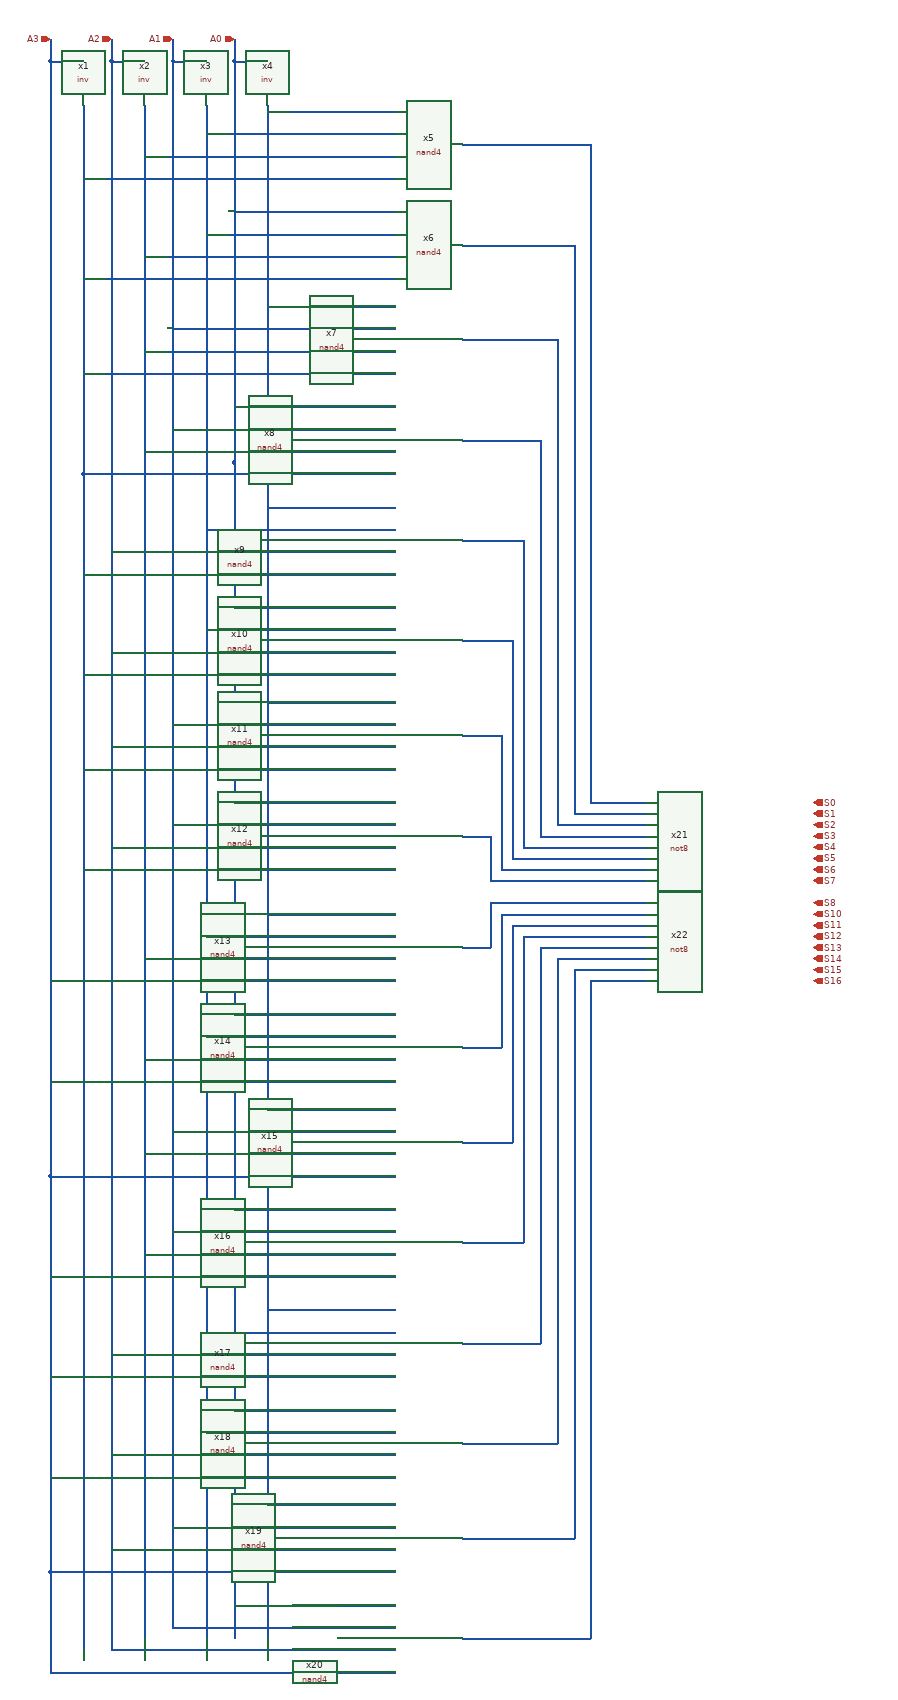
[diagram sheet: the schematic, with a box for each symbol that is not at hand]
v {xschem version=3.4.6 file_version=1.2}
G {}
K {}
V {}
S {}
E {}
N -230 -310 -230 -270 {lab=A3}
N -230 -270 -170 -270 {lab=A3}
N -120 -310 -120 -270 {lab=A2}
N -110 -270 -60 -270 {lab=A2}
N -10 -310 -10 -270 {lab=A1}
N -0 -270 50 -270 {lab=A1}
N 100 -310 100 -270 {lab=A0}
N 110 -270 160 -270 {lab=A0}
N -230 -270 -230 270 {lab=A3}
N -170 -190 -170 260 {lab=#net1}
N -170 260 -170 270 {lab=#net1}
N -120 -270 -120 270 {lab=A2}
N -60 -190 -60 260 {lab=#net2}
N -60 260 -60 270 {lab=#net2}
N 50 -190 50 260 {lab=#net3}
N 50 260 50 270 {lab=#net3}
N 100 -270 100 270 {lab=A0}
N 100 -270 110 -270 {lab=A0}
N -10 -270 0 -270 {lab=A1}
N -120 -270 -110 -270 {lab=A2}
N 160 -190 160 260 {lab=#net4}
N 160 260 160 270 {lab=#net4}
N 160 -180 390 -180 {lab=#net4}
N 50 -140 390 -140 {lab=#net3}
N -60 -100 390 -100 {lab=#net2}
N -170 -60 390 -60 {lab=#net1}
N 100 -0 390 0 {lab=A0}
N 50 40 390 40 {lab=#net3}
N -60 80 390 80 {lab=#net2}
N -170 120 390 120 {lab=#net1}
N 160 170 390 170 {lab=#net4}
N -10 210 390 210 {lab=A1}
N 160 270 160 450 {lab=#net4}
N 100 270 100 450 {lab=A0}
N 50 270 50 450 {lab=#net3}
N -60 270 -60 450 {lab=#net2}
N -120 270 -120 440 {lab=A2}
N -170 270 -170 440 {lab=#net1}
N -230 270 -230 440 {lab=A3}
N -170 290 390 290 {lab=#net1}
N -60 250 390 250 {lab=#net2}
N 100 350 390 350 {lab=A0}
N -10 390 390 390 {lab=A1}
N -60 430 390 430 {lab=#net2}
N -160 470 390 470 {lab=#net1}
N -170 440 -170 470 {lab=#net1}
N -170 470 -160 470 {lab=#net1}
N -230 440 -230 1730 {lab=A3}
N -10 -270 -10 30 {lab=A1}
N 160 530 390 530 {lab=#net4}
N 50 570 390 570 {lab=#net3}
N -120 610 390 610 {lab=A2}
N -170 650 390 650 {lab=#net1}
N -120 790 390 790 {lab=A2}
N -170 830 390 830 {lab=#net1}
N -120 960 390 960 {lab=A2}
N -170 1000 390 1000 {lab=#net1}
N -230 1730 -230 1750 {lab=A3}
N -120 1140 390 1140 {lab=A2}
N -170 1180 390 1180 {lab=#net1}
N 160 530 390 530 {lab=#net4}
N 50 570 390 570 {lab=#net3}
N 100 710 390 710 {lab=A0}
N 50 750 390 750 {lab=#net3}
N 160 880 390 880 {lab=#net4}
N -10 920 390 920 {lab=A1}
N 100 1060 390 1060 {lab=A0}
N -10 1100 390 1100 {lab=A1}
N 160 1260 390 1260 {lab=#net4}
N 50 1300 390 1300 {lab=#net3}
N -60 1340 390 1340 {lab=#net2}
N 100 1440 390 1440 {lab=A0}
N 50 1480 390 1480 {lab=#net3}
N -60 1520 390 1520 {lab=#net2}
N 160 1610 390 1610 {lab=#net4}
N -10 1650 390 1650 {lab=A1}
N -60 1690 390 1690 {lab=#net2}
N 100 1790 390 1790 {lab=A0}
N -10 1830 390 1830 {lab=A1}
N -60 1870 390 1870 {lab=#net2}
N 160 1970 390 1970 {lab=#net4}
N 50 2010 390 2010 {lab=#net3}
N -120 2050 390 2050 {lab=A2}
N -120 2230 390 2230 {lab=A2}
N -120 2400 390 2400 {lab=A2}
N -120 2580 390 2580 {lab=A2}
N 160 1970 390 1970 {lab=#net4}
N 50 2010 390 2010 {lab=#net3}
N 100 2150 390 2150 {lab=A0}
N 50 2190 390 2190 {lab=#net3}
N 160 2320 390 2320 {lab=#net4}
N -10 2360 390 2360 {lab=A1}
N 100 2500 390 2500 {lab=A0}
N -10 2540 390 2540 {lab=A1}
N -230 1380 390 1380 {lab=A3}
N -230 1560 390 1560 {lab=A3}
N -170 470 -170 2580 {lab=#net1}
N -120 440 -120 2550 {lab=A2}
N -60 450 -60 2560 {lab=#net2}
N 50 450 50 2560 {lab=#net3}
N 100 450 100 2560 {lab=A0}
N 160 450 160 2560 {lab=#net4}
N 100 450 100 2560 {lab=A0}
N -10 30 -10 2140 {lab=A1}
N -10 2140 -10 2540 {lab=A1}
N -120 2550 -120 2580 {lab=A2}
N -230 2440 390 2440 {lab=A3}
N -230 2270 390 2270 {lab=A3}
N -230 2090 390 2090 {lab=A3}
N -230 1910 390 1910 {lab=A3}
N -230 1730 390 1730 {lab=A3}
N -230 1750 -230 2440 {lab=A3}
N -220 2620 390 2620 {lab=A3}
N -230 2620 -220 2620 {lab=A3}
N -230 2440 -230 2620 {lab=A3}
N 510 1120 560 1120 {lab=#net5}
N 560 1200 840 1200 {lab=#net5}
N 560 1120 560 1200 {lab=#net5}
N 580 1180 840 1180 {lab=#net6}
N 510 940 580 940 {lab=#net6}
N 580 940 580 1180 {lab=#net6}
N 600 1160 840 1160 {lab=#net7}
N 600 770 600 1160 {lab=#net7}
N 510 770 600 770 {lab=#net7}
N 510 590 620 590 {lab=#net8}
N 510 410 650 410 {lab=#net9}
N 510 230 680 230 {lab=#net10}
N 510 60 710 60 {lab=#net11}
N 510 -120 740 -120 {lab=#net12}
N 740 -120 740 1060 {lab=#net12}
N 740 1060 840 1060 {lab=#net12}
N 620 1140 840 1140 {lab=#net8}
N 650 1120 840 1120 {lab=#net9}
N 680 1100 840 1100 {lab=#net10}
N 620 590 620 1140 {lab=#net8}
N 650 410 650 1120 {lab=#net9}
N 680 230 680 1100 {lab=#net10}
N 710 60 710 1080 {lab=#net11}
N 710 1080 840 1080 {lab=#net11}
N 510 1320 560 1320 {lab=#net13}
N 560 1240 840 1240 {lab=#net13}
N 560 1240 560 1320 {lab=#net13}
N 580 1260 840 1260 {lab=#net14}
N 510 1500 580 1500 {lab=#net14}
N 580 1260 580 1500 {lab=#net14}
N 600 1280 840 1280 {lab=#net15}
N 600 1280 600 1670 {lab=#net15}
N 510 1670 600 1670 {lab=#net15}
N 510 1850 620 1850 {lab=#net16}
N 510 2030 650 2030 {lab=#net17}
N 510 2210 680 2210 {lab=#net18}
N 510 2380 710 2380 {lab=#net19}
N 510 2560 740 2560 {lab=#net20}
N 740 1380 740 2560 {lab=#net20}
N 740 1380 840 1380 {lab=#net20}
N 620 1300 840 1300 {lab=#net16}
N 650 1320 840 1320 {lab=#net17}
N 680 1340 840 1340 {lab=#net18}
N 620 1300 620 1850 {lab=#net16}
N 650 1320 650 2030 {lab=#net17}
N 680 1340 680 2210 {lab=#net18}
N 710 1360 710 2380 {lab=#net19}
N 710 1360 840 1360 {lab=#net19}
C {INV/inv.sym} -170 -230 1 0 {name=x1 VSS=VSS VDD=VDD}
C {INV/inv.sym} -60 -230 1 0 {name=x2 VSS=VSS VDD=VDD}
C {INV/inv.sym} 50 -230 1 0 {name=x3 VSS=VSS VDD=VDD}
C {INV/inv.sym} 160 -230 1 0 {name=x4 VSS=VSS VDD=VDD}
C {devices/ipin.sym} 100 -310 1 0 {name=p9 lab=A0}
C {devices/ipin.sym} -10 -310 1 0 {name=p11 lab=A1}
C {devices/ipin.sym} -120 -310 1 0 {name=p13 lab=A2}
C {devices/ipin.sym} -230 -310 1 0 {name=p15 lab=A3}
C {NAND/nand4.sym} 450 -120 0 0 {name=x5 VSS=VSS VDD=VDD}
C {NAND/nand4.sym} 450 60 0 0 {name=x6 VSS=VSS VDD=VDD}
C {NAND/nand4.sym} 450 230 0 0 {name=x7 VSS=VSS VDD=VDD}
C {NAND/nand4.sym} 450 410 0 0 {name=x8 VSS=VSS VDD=VDD}
C {NAND/nand4.sym} 450 590 0 0 {name=x9 VSS=VSS VDD=VDD}
C {NAND/nand4.sym} 450 770 0 0 {name=x10 VSS=VSS VDD=VDD}
C {NAND/nand4.sym} 450 940 0 0 {name=x11 VSS=VSS VDD=VDD}
C {NAND/nand4.sym} 450 1120 0 0 {name=x12 VSS=VSS VDD=VDD}
C {NAND/nand4.sym} 450 1320 0 0 {name=x13 VSS=VSS VDD=VDD}
C {NAND/nand4.sym} 450 1500 0 0 {name=x14 VSS=VSS VDD=VDD}
C {NAND/nand4.sym} 450 1670 0 0 {name=x15 VSS=VSS VDD=VDD}
C {NAND/nand4.sym} 450 1850 0 0 {name=x16 VSS=VSS VDD=VDD}
C {NAND/nand4.sym} 450 2030 0 0 {name=x17 VSS=VSS VDD=VDD}
C {NAND/nand4.sym} 450 2210 0 0 {name=x18 VSS=VSS VDD=VDD}
C {NAND/nand4.sym} 450 2380 0 0 {name=x19 VSS=VSS VDD=VDD}
C {NAND/nand4.sym} 450 2560 0 0 {name=x20 VSS=VSS VDD=VDD}
C {devices/opin.sym} 1140 1180 0 0 {name=p7 lab=S6}
C {devices/opin.sym} 1140 1200 0 0 {name=p8 lab=S7}
C {devices/opin.sym} 1140 1120 0 0 {name=p4 lab=S3}
C {devices/opin.sym} 1140 1140 0 0 {name=p5 lab=S4}
C {devices/opin.sym} 1140 1160 0 0 {name=p6 lab=S5}
C {devices/opin.sym} 1140 1060 0 0 {name=p1 lab=S0}
C {devices/opin.sym} 1140 1080 0 0 {name=p2 lab=S1}
C {devices/opin.sym} 1140 1100 0 0 {name=p3 lab=S2}
C {NOT/not8.sym} 990 1130 0 0 {name=x21 VSS=VSS VDD=VDD}
C {devices/opin.sym} 1140 1360 0 0 {name=p10 lab=S15}
C {devices/opin.sym} 1140 1380 0 0 {name=p12 lab=S16}
C {devices/opin.sym} 1140 1300 0 0 {name=p14 lab=S12}
C {devices/opin.sym} 1140 1320 0 0 {name=p16 lab=S13}
C {devices/opin.sym} 1140 1340 0 0 {name=p17 lab=S14}
C {devices/opin.sym} 1140 1240 0 0 {name=p18 lab=S8}
C {devices/opin.sym} 1140 1260 0 0 {name=p19 lab=S10}
C {devices/opin.sym} 1140 1280 0 0 {name=p20 lab=S11}
C {NOT/not8.sym} 990 1310 0 0 {name=x22 VSS=VSS VDD=VDD}
